VERSION 5.7 ;
  NOWIREEXTENSIONATPIN ON ;
  DIVIDERCHAR "/" ;
  BUSBITCHARS "[]" ;
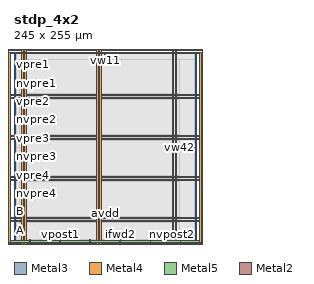
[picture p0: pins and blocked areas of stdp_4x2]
MACRO stdp_4x2
  CLASS BLOCK ;
  FOREIGN stdp_4x2 ;
  ORIGIN 0.000 0.000 ;
  SIZE 245.000 BY 255.000 ;
  PIN A
    DIRECTION INOUT ;
    USE SIGNAL ;
    ANTENNAGATEAREA 213.664001 ;
    PORT
      LAYER Metal3 ;
        RECT 0.000 15.680 3.000 16.240 ;
    END
  END A
  PIN B
    DIRECTION INOUT ;
    USE SIGNAL ;
    ANTENNAGATEAREA 246.879990 ;
    PORT
      LAYER Metal3 ;
        RECT 0.000 40.320 3.000 40.880 ;
    END
  END B
  PIN avdd
    DIRECTION INOUT ;
    USE POWER ;
    PORT
      LAYER Metal4 ;
        RECT -6.880 -0.160 -4.880 254.960 ;
    END
    PORT
      LAYER Metal4 ;
        RECT 249.600 -0.160 251.600 254.960 ;
    END
    PORT
      LAYER Metal5 ;
        RECT -6.880 -0.160 251.600 1.840 ;
    END
    PORT
      LAYER Metal5 ;
        RECT -6.880 252.960 251.600 254.960 ;
    END
    PORT
      LAYER Metal4 ;
        RECT 10.120 -3.660 12.120 258.460 ;
    END
    PORT
      LAYER Metal4 ;
        RECT 111.120 -3.660 113.120 258.460 ;
    END
    PORT
      LAYER Metal4 ;
        RECT 212.120 -3.660 214.120 258.460 ;
    END
    PORT
      LAYER Metal5 ;
        RECT -10.380 27.340 255.100 29.340 ;
    END
    PORT
      LAYER Metal5 ;
        RECT -10.380 82.340 255.100 84.340 ;
    END
    PORT
      LAYER Metal5 ;
        RECT -10.380 137.340 255.100 139.340 ;
    END
    PORT
      LAYER Metal5 ;
        RECT -10.380 192.340 255.100 194.340 ;
    END
  END avdd
  PIN avss
    DIRECTION INOUT ;
    USE GROUND ;
    PORT
      LAYER Metal4 ;
        RECT -10.380 -3.660 -8.380 258.460 ;
    END
    PORT
      LAYER Metal4 ;
        RECT 253.100 -3.660 255.100 258.460 ;
    END
    PORT
      LAYER Metal5 ;
        RECT -10.380 -3.660 255.100 -1.660 ;
    END
    PORT
      LAYER Metal5 ;
        RECT -10.380 256.460 255.100 258.460 ;
    END
    PORT
      LAYER Metal4 ;
        RECT 14.120 -3.660 16.120 258.460 ;
    END
    PORT
      LAYER Metal4 ;
        RECT 115.120 -3.660 117.120 258.460 ;
    END
    PORT
      LAYER Metal4 ;
        RECT 216.120 -3.660 218.120 258.460 ;
    END
    PORT
      LAYER Metal5 ;
        RECT -10.380 31.340 255.100 33.340 ;
    END
    PORT
      LAYER Metal5 ;
        RECT -10.380 86.340 255.100 88.340 ;
    END
    PORT
      LAYER Metal5 ;
        RECT -10.380 141.340 255.100 143.340 ;
    END
    PORT
      LAYER Metal5 ;
        RECT -10.380 196.340 255.100 198.340 ;
    END
  END avss
  PIN ifwd1
    DIRECTION OUTPUT ;
    USE SIGNAL ;
    ANTENNAGATEAREA 2.500000 ;
    ANTENNADIFFAREA 0.300000 ;
    PORT
      LAYER Metal2 ;
        RECT 21.280 0.000 21.840 3.000 ;
    END
  END ifwd1
  PIN ifwd2
    DIRECTION OUTPUT ;
    USE SIGNAL ;
    ANTENNAGATEAREA 2.500000 ;
    ANTENNADIFFAREA 0.300000 ;
    PORT
      LAYER Metal2 ;
        RECT 142.240 0.000 142.800 3.000 ;
    END
  END ifwd2
  PIN nvpost1
    DIRECTION INPUT ;
    USE SIGNAL ;
    ANTENNAGATEAREA 1.260000 ;
    PORT
      LAYER Metal2 ;
        RECT 101.920 0.000 102.480 3.000 ;
    END
  END nvpost1
  PIN nvpost2
    DIRECTION INPUT ;
    USE SIGNAL ;
    ANTENNAGATEAREA 1.260000 ;
    PORT
      LAYER Metal2 ;
        RECT 222.880 0.000 223.440 3.000 ;
    END
  END nvpost2
  PIN nvpre1
    DIRECTION INPUT ;
    USE SIGNAL ;
    ANTENNAGATEAREA 0.630000 ;
    PORT
      LAYER Metal3 ;
        RECT 0.000 212.800 3.000 213.360 ;
    END
  END nvpre1
  PIN nvpre2
    DIRECTION INPUT ;
    USE SIGNAL ;
    ANTENNAGATEAREA 0.630000 ;
    PORT
      LAYER Metal3 ;
        RECT 0.000 163.520 3.000 164.080 ;
    END
  END nvpre2
  PIN nvpre3
    DIRECTION INPUT ;
    USE SIGNAL ;
    ANTENNAGATEAREA 0.630000 ;
    PORT
      LAYER Metal3 ;
        RECT 0.000 114.240 3.000 114.800 ;
    END
  END nvpre3
  PIN nvpre4
    DIRECTION INPUT ;
    USE SIGNAL ;
    ANTENNAGATEAREA 0.630000 ;
    PORT
      LAYER Metal3 ;
        RECT 0.000 64.960 3.000 65.520 ;
    END
  END nvpre4
  PIN vpost1
    DIRECTION INPUT ;
    USE SIGNAL ;
    ANTENNAGATEAREA 1.260000 ;
    PORT
      LAYER Metal2 ;
        RECT 61.600 0.000 62.160 3.000 ;
    END
  END vpost1
  PIN vpost2
    DIRECTION INPUT ;
    USE SIGNAL ;
    ANTENNAGATEAREA 1.260000 ;
    PORT
      LAYER Metal2 ;
        RECT 182.560 0.000 183.120 3.000 ;
    END
  END vpost2
  PIN vpre1
    DIRECTION INPUT ;
    USE SIGNAL ;
    ANTENNAGATEAREA 0.630000 ;
    PORT
      LAYER Metal3 ;
        RECT 0.000 237.440 3.000 238.000 ;
    END
  END vpre1
  PIN vpre2
    DIRECTION INPUT ;
    USE SIGNAL ;
    ANTENNAGATEAREA 0.630000 ;
    PORT
      LAYER Metal3 ;
        RECT 0.000 188.160 3.000 188.720 ;
    END
  END vpre2
  PIN vpre3
    DIRECTION INPUT ;
    USE SIGNAL ;
    ANTENNAGATEAREA 0.630000 ;
    PORT
      LAYER Metal3 ;
        RECT 0.000 138.880 3.000 139.440 ;
    END
  END vpre3
  PIN vpre4
    DIRECTION INPUT ;
    USE SIGNAL ;
    ANTENNAGATEAREA 0.630000 ;
    PORT
      LAYER Metal3 ;
        RECT 0.000 89.600 3.000 90.160 ;
    END
  END vpre4
  PIN vw11
    DIRECTION INOUT ;
    USE SIGNAL ;
    ANTENNAGATEAREA 7.500000 ;
    ANTENNADIFFAREA 0.600000 ;
    PORT
      LAYER Metal2 ;
        RECT 122.080 252.000 122.640 255.000 ;
    END
  END vw11
  PIN vw42
    DIRECTION INOUT ;
    USE SIGNAL ;
    ANTENNAGATEAREA 7.500000 ;
    ANTENNADIFFAREA 0.600000 ;
    PORT
      LAYER Metal3 ;
        RECT 242.000 126.560 245.000 127.120 ;
    END
  END vw42
  OBS
      LAYER Nwell ;
        RECT 26.000 5.800 214.810 237.155 ;
      LAYER Metal1 ;
        RECT 26.230 6.010 214.600 245.105 ;
      LAYER Metal2 ;
        RECT 23.900 3.300 214.600 245.105 ;
        RECT 23.900 3.250 61.300 3.300 ;
        RECT 62.460 3.250 101.620 3.300 ;
        RECT 102.780 3.250 141.940 3.300 ;
        RECT 143.100 3.250 182.260 3.300 ;
        RECT 183.420 3.250 214.600 3.300 ;
      LAYER Metal3 ;
        RECT 3.000 238.300 242.000 252.420 ;
        RECT 3.300 237.140 242.000 238.300 ;
        RECT 3.000 213.660 242.000 237.140 ;
        RECT 3.300 212.500 242.000 213.660 ;
        RECT 3.000 189.020 242.000 212.500 ;
        RECT 3.300 187.860 242.000 189.020 ;
        RECT 3.000 164.380 242.000 187.860 ;
        RECT 3.300 163.220 242.000 164.380 ;
        RECT 3.000 139.740 242.000 163.220 ;
        RECT 3.300 138.580 242.000 139.740 ;
        RECT 3.000 127.420 242.000 138.580 ;
        RECT 3.000 126.260 241.700 127.420 ;
        RECT 3.000 115.100 242.000 126.260 ;
        RECT 3.300 113.940 242.000 115.100 ;
        RECT 3.000 90.460 242.000 113.940 ;
        RECT 3.300 89.300 242.000 90.460 ;
        RECT 3.000 65.820 242.000 89.300 ;
        RECT 3.300 64.660 242.000 65.820 ;
        RECT 3.000 41.180 242.000 64.660 ;
        RECT 3.300 40.020 242.000 41.180 ;
        RECT 3.000 16.540 242.000 40.020 ;
        RECT 3.300 15.380 242.000 16.540 ;
        RECT 3.000 0.140 242.000 15.380 ;
      LAYER Metal4 ;
        RECT 7.420 0.090 9.820 245.105 ;
        RECT 12.420 0.090 13.820 245.105 ;
        RECT 16.420 0.090 110.820 245.105 ;
        RECT 113.420 0.090 114.820 245.105 ;
        RECT 117.420 0.090 211.820 245.105 ;
        RECT 214.420 0.090 215.820 245.105 ;
        RECT 218.420 0.090 241.780 245.105 ;
      LAYER Metal5 ;
        RECT 7.340 198.940 221.980 245.355 ;
        RECT 7.340 194.940 221.980 195.740 ;
        RECT 7.340 143.940 221.980 191.740 ;
        RECT 7.340 139.940 221.980 140.740 ;
        RECT 7.340 88.940 221.980 136.740 ;
        RECT 7.340 84.940 221.980 85.740 ;
        RECT 7.340 33.940 221.980 81.740 ;
        RECT 7.340 29.940 221.980 30.740 ;
        RECT 7.340 3.000 221.980 26.740 ;
  END
END stdp_4x2
END LIBRARY

